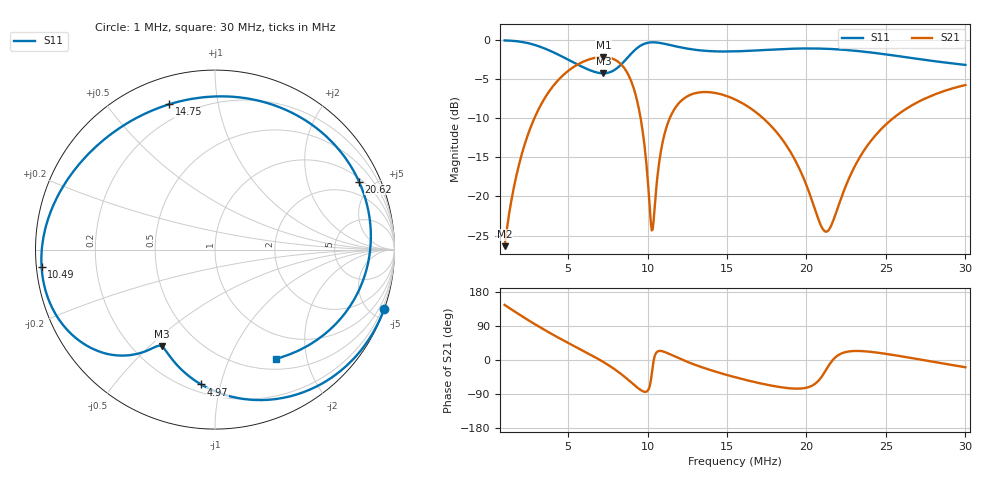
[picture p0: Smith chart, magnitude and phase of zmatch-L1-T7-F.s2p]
# HZ S RI R 50
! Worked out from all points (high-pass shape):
!   505 points, 1 MHz to 30 MHz, reference 50 ohm
!   highest |S21| = -2.13 dB at 7.214 MHz (marker M1); lowest = -26.4 dB at 1 MHz (marker M2)
!   |S21| within 3 dB of the highest: 4.356 MHz to 8.948 MHz (4.592 MHz wide, 69 % of centre)
!   lowest |S11| = -4.2 dB at 7.214 MHz (marker M3), VSWR 4.20, Z = 15.7 - j27.3 ohm
!   |S11| at or under -10 dB: nowhere
!   S12 and S22 are empty: the file has one direction only
!   S11 on the Smith chart (normalised r, x): 1 MHz: 0.02, -5.88; 4.97 MHz: 0.25, -0.87; 10.49 MHz: 0.01, -0.05; 14.75 MHz: 0.13, +0.73; 20.62 MHz: 1.17, +4.15; 30 MHz: 0.63, -1.50
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1000000  0.943 -0.3303  -0.0396 0.0272  0 0  0 0
2553580  0.6007 -0.744  -0.0612 0.2559  0 0  0 0
4970260  -0.0768 -0.7515  0.4427 0.4542  0 0  0 0
5833360  -0.2057 -0.6496  0.6444 0.3239  0 0  0 0
7214320  -0.2978 -0.5384  0.7794 -0.0716  0 0  0 0
8019880  -0.3558 -0.5529  0.6618 -0.3406  0 0  0 0
8825440  -0.5297 -0.5903  0.3488 -0.4777  0 0  0 0
9631000  -0.8165 -0.4546  0.0449 -0.2832  0 0  0 0
1.026394e7  -0.9518 -0.1982  0.0492 -0.0354  0 0  0 0
1.04941e7  -0.9662 -0.0976  0.0949 0.0262  0 0  0 0
1.066672e7  -0.9666 -0.0245  0.136 0.0586  0 0  0 0
1.118458e7  -0.9292 0.173  0.2619 0.0917  0 0  0 0
1.19326e7  -0.8183 0.3953  0.3909 0.0354  0 0  0 0
1.475206e7  -0.2535 0.81  0.3591 -0.2675  0 0  0 0
1.550008e7  -0.0914 0.8455  0.2941 -0.298  0 0  0 0
1.831954e7  0.4927 0.727  0.0776 -0.2306  0 0  0 0
2.033344e7  0.7771 0.4294  0.0355 -0.0882  0 0  0 0
2.062114e7  0.8025 0.3783  0.0389 -0.0675  0 0  0 0
2.14267e7  0.8514 0.2312  0.0601 -0.0136  0 0  0 0
2.321044e7  0.8515 -0.0815  0.1539 0.0681  0 0  0 0
2.51668e7  0.7322 -0.344  0.2894 0.0783  0 0  0 0
3.000016e7  0.3373 -0.6097  0.489 -0.17  0 0  0 0
